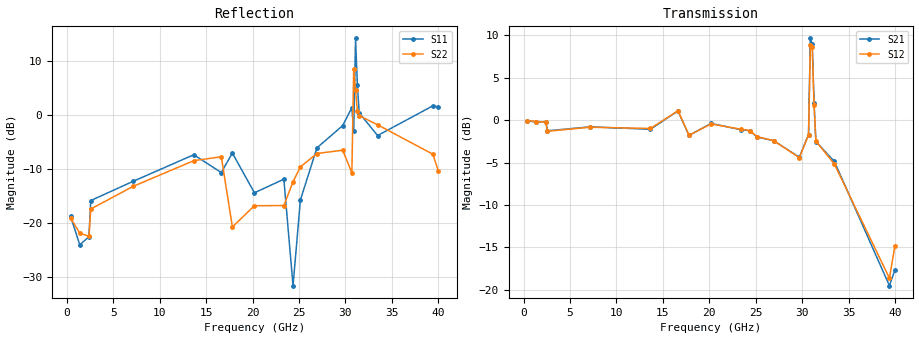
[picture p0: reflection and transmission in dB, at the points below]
! Network Analyzer HP8722ES.07.66: Jul 25, 2000 Serial No. US39175408
! 27 Oct 2004  10:46:36
! Frequency  S11  S21  S12  S22
# HZ  S  DB R  50
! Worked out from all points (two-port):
!   201 points, 400 MHz to 40 GHz, reference 50 ohm
!   highest |S21| = 9.66 dB at 30.89 GHz (marker M1); lowest = -19.5 dB at 39.41 GHz (marker M2)
!   |S21| within 3 dB of the highest: 30.84 GHz to 31.16 GHz (315.9 MHz wide, 1.02 % of centre)
!   lowest |S11| = -31.6 dB at 24.36 GHz (marker M3), VSWR 1.05, Z = 52.6 - j0.647 ohm
!   |S11| at or under -10 dB: start of sweep to 8.673 GHz; 16.57 GHz to 17.14 GHz (566.5 MHz wide, 3.36 % of centre); 18.51 GHz to 25.81 GHz (7.299 GHz wide, 32.9 % of centre)
!   |S22| runs from -23.1 to 8.5 dB; largest |S21 - S12| = 1.2
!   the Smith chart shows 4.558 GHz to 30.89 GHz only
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4e8  -18.79 -92.7  -0.09 3.7  -0.04 4.6  -19.07 -88.4
1.39e9  -24.05 -94.3  -0.21 -2.7  -0.16 -3.1  -21.90 -90.6
2.38e9  -22.55 -86.6  -0.18 -8.1  -0.22 -7.9  -22.47 -103.2
2.578e9  -15.84 -50.4  -1.25 -8.5  -1.31 -7.7  -17.41 -38.8
7.132e9  -12.28 -91.6  -0.79 -21.2  -0.83 -22.0  -13.22 -110.7
1.3666e10  -7.35 -99.1  -1.07 -29.4  -0.98 -29.7  -8.45 -136.0
1.6636e10  -10.65 -110.0  1.09 -43.7  1.11 -44.0  -7.72 163.3
1.7824e10  -7.03 -87.2  -1.80 -45.3  -1.78 -45.7  -20.74 145.8
2.02e10  -14.41 -68.8  -0.39 -50.6  -0.44 -51.2  -16.80 119.9
2.3368e10  -11.88 -43.1  -1.11 -67.2  -1.06 -67.7  -16.77 45.6
2.4358e10  -31.63 -13.6  -1.25 -72.6  -1.22 -73.7  -12.36 36.3
2.515e10  -15.73 75.4  -1.99 -76.5  -1.94 -77.8  -9.61 21.8
2.6932e10  -6.07 45.4  -2.42 -77.1  -2.41 -79.1  -7.12 -6.3
2.9704e10  -1.95 35.8  -4.37 -93.3  -4.43 -94.0  -6.51 -43.3
3.0694e10  1.39 34.2  -1.70 -79.9  -1.74 -81.0  -10.69 -167.8
3.0892e10  -3.03 -168.0  9.66 92.7  8.91 70.0  8.53 -24.8
3.109e10  14.23 -10.0  8.99 -46.4  8.66 -48.5  4.61 -84.8
3.1288e10  5.51 -34.6  1.98 -50.8  1.81 -52.9  0.78 -49.6
3.1486e10  0.40 -23.2  -2.53 -56.4  -2.47 -59.5  -0.10 -33.4
3.3466e10  -3.79 -11.4  -4.86 -93.0  -5.16 -95.2  -1.80 -47.9
3.9406e10  1.71 -14.5  -19.54 -95.3  -18.65 -60.7  -7.24 -112.9
4e10  1.52 -19.3  -17.67 -65.1  -14.80 -51.6  -10.29 -104.7
